VERSION 5.8 ;
BUSBITCHARS "[]" ;
DIVIDERCHAR "/" ;
UNITS
    DATABASE MICRONS 1000 ;
END UNITS

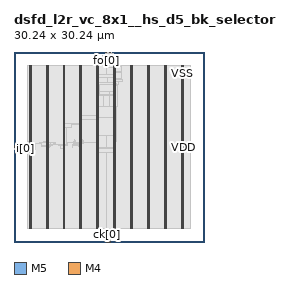
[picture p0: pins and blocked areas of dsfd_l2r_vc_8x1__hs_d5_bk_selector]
MACRO dsfd_l2r_vc_8x1__hs_d5_bk_selector
  FOREIGN dsfd_l2r_vc_8x1__hs_d5_bk_selector 0 0 ;
  CLASS BLOCK ;
  SIZE 30.24 BY 30.24 ;
  PIN ck[0]
    DIRECTION INPUT ;
    USE SIGNAL ;
    PORT
      LAYER M5 ;
        RECT  14.784 0 14.808 0.084 ;
    END
  END ck[0]
  PIN cks[0]
    DIRECTION INPUT ;
    USE SIGNAL ;
    PORT
      LAYER M5 ;
        RECT  14.976 0 15 0.084 ;
    END
  END cks[0]
  PIN fo[0]
    DIRECTION OUTPUT ;
    USE SIGNAL ;
    PORT
      LAYER M5 ;
        RECT  14.64 30.156 14.664 30.24 ;
    END
  END fo[0]
  PIN i[0]
    DIRECTION INPUT ;
    USE SIGNAL ;
    PORT
      LAYER M4 ;
        RECT  0 14.88 0.084 14.904 ;
    END
  END i[0]
  PIN i[1]
    DIRECTION INPUT ;
    USE SIGNAL ;
    PORT
      LAYER M4 ;
        RECT  0 14.928 0.084 14.952 ;
    END
  END i[1]
  PIN i[2]
    DIRECTION INPUT ;
    USE SIGNAL ;
    PORT
      LAYER M4 ;
        RECT  0 14.976 0.084 15 ;
    END
  END i[2]
  PIN i[3]
    DIRECTION INPUT ;
    USE SIGNAL ;
    PORT
      LAYER M4 ;
        RECT  0 15.024 0.084 15.048 ;
    END
  END i[3]
  PIN i[4]
    DIRECTION INPUT ;
    USE SIGNAL ;
    PORT
      LAYER M4 ;
        RECT  0 15.072 0.084 15.096 ;
    END
  END i[4]
  PIN i[5]
    DIRECTION INPUT ;
    USE SIGNAL ;
    PORT
      LAYER M4 ;
        RECT  0 15.12 0.084 15.144 ;
    END
  END i[5]
  PIN i[6]
    DIRECTION INPUT ;
    USE SIGNAL ;
    PORT
      LAYER M4 ;
        RECT  0 15.168 0.084 15.192 ;
    END
  END i[6]
  PIN i[7]
    DIRECTION INPUT ;
    USE SIGNAL ;
    PORT
      LAYER M4 ;
        RECT  0 15.216 0.084 15.24 ;
    END
  END i[7]
  PIN i[8]
    DIRECTION INPUT ;
    USE SIGNAL ;
    PORT
      LAYER M4 ;
        RECT  0 15.264 0.084 15.288 ;
    END
  END i[8]
  PIN od[0]
    DIRECTION OUTPUT ;
    USE SIGNAL ;
    PORT
      LAYER M5 ;
        RECT  14.832 30.156 14.856 30.24 ;
    END
  END od[0]
  PIN od[1]
    DIRECTION OUTPUT ;
    USE SIGNAL ;
    PORT
      LAYER M5 ;
        RECT  14.88 30.156 14.904 30.24 ;
    END
  END od[1]
  PIN od[2]
    DIRECTION OUTPUT ;
    USE SIGNAL ;
    PORT
      LAYER M5 ;
        RECT  14.928 30.156 14.952 30.24 ;
    END
  END od[2]
  PIN od[3]
    DIRECTION OUTPUT ;
    USE SIGNAL ;
    PORT
      LAYER M5 ;
        RECT  14.976 30.156 15 30.24 ;
    END
  END od[3]
  PIN od[4]
    DIRECTION OUTPUT ;
    USE SIGNAL ;
    PORT
      LAYER M5 ;
        RECT  15.024 30.156 15.048 30.24 ;
    END
  END od[4]
  PIN od[5]
    DIRECTION OUTPUT ;
    USE SIGNAL ;
    PORT
      LAYER M5 ;
        RECT  15.072 30.156 15.096 30.24 ;
    END
  END od[5]
  PIN od[6]
    DIRECTION OUTPUT ;
    USE SIGNAL ;
    PORT
      LAYER M5 ;
        RECT  15.12 30.156 15.144 30.24 ;
    END
  END od[6]
  PIN od[7]
    DIRECTION OUTPUT ;
    USE SIGNAL ;
    PORT
      LAYER M5 ;
        RECT  15.168 30.156 15.192 30.24 ;
    END
  END od[7]
  PIN od[8]
    DIRECTION OUTPUT ;
    USE SIGNAL ;
    PORT
      LAYER M5 ;
        RECT  15.216 30.156 15.24 30.24 ;
    END
  END od[8]
  PIN od[9]
    DIRECTION OUTPUT ;
    USE SIGNAL ;
    PORT
      LAYER M5 ;
        RECT  15.264 30.156 15.288 30.24 ;
    END
  END od[9]
  PIN rs[0]
    DIRECTION INPUT ;
    USE SIGNAL ;
    PORT
      LAYER M5 ;
        RECT  15.168 0 15.192 0.084 ;
    END
  END rs[0]
  PIN rss[0]
    DIRECTION INPUT ;
    USE SIGNAL ;
    PORT
      LAYER M5 ;
        RECT  15.36 0 15.384 0.084 ;
    END
  END rss[0]
  PIN st[0]
    DIRECTION OUTPUT ;
    USE SIGNAL ;
    PORT
      LAYER M5 ;
        RECT  15.456 30.156 15.48 30.24 ;
    END
  END st[0]
  PIN st[1]
    DIRECTION OUTPUT ;
    USE SIGNAL ;
    PORT
      LAYER M5 ;
        RECT  15.504 30.156 15.528 30.24 ;
    END
  END st[1]
  PIN st[2]
    DIRECTION OUTPUT ;
    USE SIGNAL ;
    PORT
      LAYER M5 ;
        RECT  15.552 30.156 15.576 30.24 ;
    END
  END st[2]
  PIN VDD
    DIRECTION INOUT ;
    USE POWER ;
    PORT
      LAYER M5 ;
        RECT  26.892 2.151 27.012 28.089 ;
        RECT  24.192 2.151 24.312 28.089 ;
        RECT  21.492 2.151 21.612 28.089 ;
        RECT  18.792 2.151 18.912 28.089 ;
        RECT  16.092 2.151 16.212 28.089 ;
        RECT  13.392 2.151 13.512 28.089 ;
        RECT  10.692 2.151 10.812 28.089 ;
        RECT  7.992 2.151 8.112 28.089 ;
        RECT  5.292 2.151 5.412 28.089 ;
        RECT  2.592 2.151 2.712 28.089 ;
    END
  END VDD
  PIN VSS
    DIRECTION INOUT ;
    USE GROUND ;
    PORT
      LAYER M5 ;
        RECT  26.7 2.137 26.82 28.103 ;
        RECT  24 2.137 24.12 28.103 ;
        RECT  21.3 2.137 21.42 28.103 ;
        RECT  18.6 2.137 18.72 28.103 ;
        RECT  15.9 2.137 16.02 28.103 ;
        RECT  13.2 2.137 13.32 28.103 ;
        RECT  10.5 2.137 10.62 28.103 ;
        RECT  7.8 2.137 7.92 28.103 ;
        RECT  5.1 2.137 5.22 28.103 ;
        RECT  2.4 2.137 2.52 28.103 ;
    END
  END VSS
  # OT_OBS_CLOSED layer=M5 d_um=1.536 added=13
  OBS
    LAYER RVTN ;
     RECT  2.16 2.16 28.08 2.295 ;
     RECT  2.16 2.565 28.08 2.835 ;
     RECT  2.16 3.105 28.08 3.375 ;
     RECT  2.16 3.645 28.08 3.915 ;
     RECT  2.16 4.185 28.08 4.455 ;
     RECT  2.16 4.725 28.08 4.995 ;
     RECT  2.16 5.265 28.08 5.535 ;
     RECT  2.16 5.805 28.08 6.075 ;
     RECT  2.16 6.345 28.08 6.615 ;
     RECT  2.16 6.885 28.08 7.155 ;
     RECT  2.16 7.425 28.08 7.695 ;
     RECT  2.16 7.965 28.08 8.235 ;
     RECT  2.16 8.505 28.08 8.775 ;
     RECT  2.16 9.045 28.08 9.315 ;
     RECT  2.16 9.585 28.08 9.855 ;
     RECT  2.16 10.125 28.08 10.395 ;
     RECT  2.16 10.665 28.08 10.935 ;
     RECT  2.16 11.205 28.08 11.475 ;
     RECT  2.16 11.745 28.08 12.015 ;
     RECT  2.16 12.285 28.08 12.555 ;
     RECT  2.16 12.825 28.08 13.095 ;
     RECT  2.16 13.365 28.08 13.635 ;
     RECT  2.16 13.905 28.08 14.175 ;
     RECT  2.16 14.445 28.08 14.715 ;
     RECT  2.16 14.985 28.08 15.255 ;
     RECT  2.16 15.525 28.08 15.795 ;
     RECT  2.16 16.065 28.08 16.335 ;
     RECT  2.16 16.605 28.08 16.875 ;
     RECT  2.16 17.145 28.08 17.415 ;
     RECT  2.16 17.685 28.08 17.955 ;
     RECT  2.16 18.225 28.08 18.495 ;
     RECT  2.16 18.765 28.08 19.035 ;
     RECT  2.16 19.305 28.08 19.575 ;
     RECT  2.16 19.845 28.08 20.115 ;
     RECT  2.16 20.385 28.08 20.655 ;
     RECT  2.16 20.925 28.08 21.195 ;
     RECT  2.16 21.465 28.08 21.735 ;
     RECT  2.16 22.005 28.08 22.275 ;
     RECT  2.16 22.545 28.08 22.815 ;
     RECT  2.16 23.085 28.08 23.355 ;
     RECT  2.16 23.625 28.08 23.895 ;
     RECT  2.16 24.165 28.08 24.435 ;
     RECT  2.16 24.705 28.08 24.975 ;
     RECT  2.16 25.245 28.08 25.515 ;
     RECT  2.16 25.785 28.08 26.055 ;
     RECT  2.16 26.325 28.08 26.595 ;
     RECT  2.16 26.865 28.08 27.135 ;
     RECT  2.16 27.405 28.08 27.675 ;
     RECT  2.16 27.945 28.08 28.08 ;
    LAYER RVTP ;
     RECT  2.16 2.295 28.08 2.565 ;
     RECT  2.16 2.835 28.08 3.105 ;
     RECT  2.16 3.375 28.08 3.645 ;
     RECT  2.16 3.915 28.08 4.185 ;
     RECT  2.16 4.455 28.08 4.725 ;
     RECT  2.16 4.995 28.08 5.265 ;
     RECT  2.16 5.535 28.08 5.805 ;
     RECT  2.16 6.075 28.08 6.345 ;
     RECT  2.16 6.615 28.08 6.885 ;
     RECT  2.16 7.155 28.08 7.425 ;
     RECT  2.16 7.695 28.08 7.965 ;
     RECT  2.16 8.235 28.08 8.505 ;
     RECT  2.16 8.775 28.08 9.045 ;
     RECT  2.16 9.315 28.08 9.585 ;
     RECT  2.16 9.855 28.08 10.125 ;
     RECT  2.16 10.395 28.08 10.665 ;
     RECT  2.16 10.935 28.08 11.205 ;
     RECT  2.16 11.475 28.08 11.745 ;
     RECT  2.16 12.015 28.08 12.285 ;
     RECT  2.16 12.555 28.08 12.825 ;
     RECT  2.16 13.095 28.08 13.365 ;
     RECT  2.16 13.635 28.08 13.905 ;
     RECT  2.16 14.175 28.08 14.445 ;
     RECT  2.16 14.715 28.08 14.985 ;
     RECT  2.16 15.255 28.08 15.525 ;
     RECT  2.16 15.795 28.08 16.065 ;
     RECT  2.16 16.335 28.08 16.605 ;
     RECT  2.16 16.875 28.08 17.145 ;
     RECT  2.16 17.415 28.08 17.685 ;
     RECT  2.16 17.955 28.08 18.225 ;
     RECT  2.16 18.495 28.08 18.765 ;
     RECT  2.16 19.035 28.08 19.305 ;
     RECT  2.16 19.575 28.08 19.845 ;
     RECT  2.16 20.115 28.08 20.385 ;
     RECT  2.16 20.655 28.08 20.925 ;
     RECT  2.16 21.195 28.08 21.465 ;
     RECT  2.16 21.735 28.08 22.005 ;
     RECT  2.16 22.275 28.08 22.545 ;
     RECT  2.16 22.815 28.08 23.085 ;
     RECT  2.16 23.355 28.08 23.625 ;
     RECT  2.16 23.895 28.08 24.165 ;
     RECT  2.16 24.435 28.08 24.705 ;
     RECT  2.16 24.975 28.08 25.245 ;
     RECT  2.16 25.515 28.08 25.785 ;
     RECT  2.16 26.055 28.08 26.325 ;
     RECT  2.16 26.595 28.08 26.865 ;
     RECT  2.16 27.135 28.08 27.405 ;
     RECT  2.16 27.675 28.08 27.945 ;
    LAYER M1 ;
     RECT  2.16 2.151 28.08 28.089 ;
    LAYER M2 ;
     RECT  0.139 14.76 0.175 14.778 ;
     RECT  0.175 14.688 0.347 15.282 ;
     RECT  0.347 14.688 0.491 15.21 ;
     RECT  0.491 14.688 2.16 14.778 ;
     RECT  2.16 2.151 28.08 28.089 ;
    LAYER M3 ;
     RECT  2.415 2.143 2.505 2.413 ;
     RECT  5.115 2.143 5.205 2.413 ;
     RECT  7.815 2.143 7.905 2.413 ;
     RECT  10.515 2.143 10.605 2.413 ;
     RECT  13.215 2.143 13.305 2.413 ;
     RECT  15.915 2.143 16.005 2.413 ;
     RECT  18.615 2.143 18.705 2.413 ;
     RECT  21.315 2.143 21.405 2.413 ;
     RECT  24.015 2.143 24.105 2.413 ;
     RECT  26.715 2.143 26.805 2.413 ;
     RECT  15.915 2.413 16.197 13.675 ;
     RECT  13.215 2.413 13.497 14.203 ;
     RECT  15.3 13.675 16.197 14.215 ;
     RECT  13.215 14.203 13.986 14.251 ;
     RECT  14.796 14.215 16.197 14.251 ;
     RECT  13.215 14.251 16.197 14.369 ;
     RECT  0.18 14.683 0.198 14.755 ;
     RECT  2.415 2.413 2.697 14.791 ;
     RECT  2.415 14.791 3.402 14.875 ;
     RECT  7.815 2.413 8.097 14.881 ;
     RECT  0.144 14.755 0.198 14.957 ;
     RECT  5.115 2.413 5.397 14.989 ;
     RECT  0.18 14.957 0.198 15.115 ;
     RECT  2.304 14.875 3.402 15.151 ;
     RECT  10.515 2.413 10.797 15.151 ;
     RECT  0.18 15.115 0.414 15.187 ;
     RECT  1.152 15.163 1.17 15.187 ;
     RECT  4.356 15.151 4.374 15.223 ;
     RECT  5.115 14.989 5.67 15.223 ;
     RECT  0.18 15.187 1.17 15.293 ;
     RECT  0.18 15.293 0.198 15.296 ;
     RECT  7.416 14.881 8.097 15.331 ;
     RECT  1.152 15.293 1.17 15.341 ;
     RECT  4.356 15.223 5.814 15.421 ;
     RECT  7.416 15.331 8.478 15.421 ;
     RECT  9.324 15.061 9.342 15.421 ;
     RECT  10.332 15.151 10.797 15.421 ;
     RECT  7.056 15.421 8.478 15.449 ;
     RECT  9.324 15.421 10.797 15.493 ;
     RECT  4.356 15.421 6.174 15.499 ;
     RECT  9.324 15.493 10.818 15.521 ;
     RECT  7.056 15.449 8.442 15.533 ;
     RECT  7.056 15.533 7.074 15.557 ;
     RECT  2.304 15.151 3.474 15.601 ;
     RECT  14.544 14.369 16.197 15.601 ;
     RECT  4.356 15.499 6.282 15.629 ;
     RECT  2.304 15.601 3.582 15.691 ;
     RECT  4.356 15.629 5.397 15.691 ;
     RECT  6.156 15.629 6.282 15.691 ;
     RECT  9.54 15.521 10.818 15.691 ;
     RECT  2.304 15.691 5.397 15.719 ;
     RECT  6.156 15.691 6.678 15.719 ;
     RECT  7.815 15.533 8.442 15.719 ;
     RECT  2.304 15.719 2.862 15.755 ;
     RECT  9.54 15.691 11.07 15.755 ;
     RECT  12.348 15.601 12.366 15.755 ;
     RECT  3.996 15.719 5.397 15.773 ;
     RECT  6.228 15.719 6.678 15.791 ;
     RECT  13.215 14.369 13.497 15.799 ;
     RECT  6.336 15.791 6.678 15.821 ;
     RECT  7.815 15.719 8.19 15.821 ;
     RECT  4.392 15.773 5.397 15.827 ;
     RECT  10.515 15.755 11.07 15.827 ;
     RECT  6.66 15.821 6.678 15.899 ;
     RECT  14.328 15.601 16.197 15.961 ;
     RECT  4.644 15.827 5.397 15.989 ;
     RECT  13.068 15.799 13.497 15.989 ;
     RECT  2.34 15.755 2.862 16.025 ;
     RECT  9.54 15.755 9.738 16.025 ;
     RECT  9.612 16.025 9.738 16.061 ;
     RECT  9.684 16.061 9.738 16.133 ;
     RECT  10.515 15.827 10.998 16.133 ;
     RECT  13.14 15.989 13.497 16.141 ;
     RECT  14.328 15.961 16.326 16.141 ;
     RECT  13.14 16.141 16.326 16.169 ;
     RECT  9.684 16.133 9.702 16.295 ;
     RECT  10.515 16.133 10.854 16.367 ;
     RECT  13.176 16.169 16.326 16.973 ;
     RECT  14.292 16.973 16.326 17.069 ;
     RECT  9.144 18.235 9.162 18.689 ;
     RECT  8.928 18.763 8.946 18.803 ;
     RECT  13.176 16.973 13.497 19.471 ;
     RECT  10.515 16.367 10.797 19.483 ;
     RECT  12.564 19.471 13.497 19.517 ;
     RECT  13.14 19.517 13.497 19.805 ;
     RECT  10.515 19.483 10.854 20.111 ;
     RECT  13.176 19.805 13.497 20.885 ;
     RECT  13.215 20.885 13.497 21.001 ;
     RECT  14.328 17.069 16.326 21.155 ;
     RECT  13.215 21.001 13.59 21.541 ;
     RECT  14.472 21.155 16.326 21.541 ;
     RECT  14.472 21.541 16.506 24.899 ;
     RECT  14.508 24.899 16.506 25.043 ;
     RECT  14.544 25.043 16.506 25.051 ;
     RECT  14.544 25.051 16.578 25.591 ;
     RECT  14.544 25.591 17.19 25.889 ;
     RECT  13.215 21.541 13.734 25.951 ;
     RECT  14.544 25.889 17.046 25.951 ;
     RECT  13.215 25.951 17.046 26.941 ;
     RECT  13.215 26.941 17.154 27.059 ;
     RECT  2.415 16.025 2.697 27.827 ;
     RECT  5.115 15.989 5.397 27.827 ;
     RECT  7.815 15.821 8.097 27.827 ;
     RECT  10.515 20.111 10.797 27.827 ;
     RECT  18.615 2.413 18.897 27.827 ;
     RECT  21.315 2.413 21.597 27.827 ;
     RECT  24.015 2.413 24.297 27.827 ;
     RECT  26.715 2.413 26.997 27.827 ;
     RECT  13.215 27.059 17.118 27.869 ;
     RECT  17.028 27.869 17.046 27.941 ;
     RECT  2.415 27.827 2.505 28.097 ;
     RECT  5.115 27.827 5.205 28.097 ;
     RECT  7.815 27.827 7.905 28.097 ;
     RECT  10.515 27.827 10.605 28.097 ;
     RECT  13.215 27.869 16.005 28.097 ;
     RECT  18.615 27.827 18.705 28.097 ;
     RECT  21.315 27.827 21.405 28.097 ;
     RECT  24.015 27.827 24.105 28.097 ;
     RECT  26.715 27.827 26.805 28.097 ;
     RECT  14.004 28.097 15.75 28.589 ;
     RECT  14.148 28.589 15.75 29.741 ;
     RECT  14.652 29.741 15.75 29.789 ;
     RECT  15.012 29.789 15.75 30.077 ;
    LAYER M4 ;
     RECT  0.06 14.88 0.133 15.288 ;
     RECT  0.133 14.88 2.408 15.384 ;
     RECT  2.408 2.148 2.512 28.092 ;
     RECT  2.512 2.418 2.704 27.822 ;
     RECT  2.704 14.976 2.765 15.336 ;
     RECT  2.765 15.264 2.873 15.336 ;
     RECT  2.873 15.264 3.413 15.288 ;
     RECT  3.985 15.744 4.381 15.768 ;
     RECT  4.381 15.744 4.417 15.816 ;
     RECT  4.417 15.36 5.108 15.816 ;
     RECT  5.108 2.148 5.212 28.092 ;
     RECT  5.212 2.418 5.404 27.822 ;
     RECT  5.404 15.456 5.825 15.816 ;
     RECT  5.825 15.504 6.365 15.816 ;
     RECT  6.365 15.504 7.808 15.528 ;
     RECT  7.808 2.148 7.912 28.092 ;
     RECT  7.912 2.418 8.104 27.822 ;
     RECT  8.104 15.504 8.387 15.816 ;
     RECT  8.104 18.24 9.173 18.792 ;
     RECT  9.173 18.768 10.357 18.792 ;
     RECT  8.387 15.792 10.508 15.816 ;
     RECT  10.357 18.768 10.508 19.608 ;
     RECT  10.508 2.148 10.612 28.092 ;
     RECT  10.612 2.418 10.804 27.822 ;
     RECT  10.804 15.792 10.973 16.104 ;
     RECT  10.973 15.792 13.093 15.816 ;
     RECT  13.093 14.928 13.208 15.816 ;
     RECT  10.804 19.488 13.208 20.088 ;
     RECT  13.208 2.148 13.312 28.092 ;
     RECT  13.312 2.418 13.504 28.092 ;
     RECT  13.504 19.776 13.619 20.088 ;
     RECT  13.504 23.328 13.708 23.736 ;
     RECT  13.504 14.208 14.041 14.952 ;
     RECT  13.504 16.944 14.243 17.64 ;
     RECT  14.137 29.712 14.425 29.736 ;
     RECT  13.504 24.864 14.569 25.032 ;
     RECT  14.041 14.928 14.573 14.952 ;
     RECT  14.425 29.664 14.597 29.736 ;
     RECT  14.597 29.664 14.636 29.784 ;
     RECT  14.243 17.616 14.645 17.64 ;
     RECT  14.636 29.616 14.723 29.784 ;
     RECT  14.641 26.736 14.725 26.76 ;
     RECT  13.619 20.064 14.819 20.088 ;
     RECT  14.569 24.864 14.821 25.416 ;
     RECT  13.993 28.56 14.821 28.584 ;
     RECT  14.723 29.664 14.917 29.784 ;
     RECT  14.821 27.792 14.965 28.584 ;
     RECT  13.708 23.328 15.109 23.448 ;
     RECT  14.821 24.864 15.109 26.136 ;
     RECT  14.965 27.312 15.155 28.584 ;
     RECT  14.917 29.664 15.251 30.072 ;
     RECT  14.957 21.6 15.253 21.624 ;
     RECT  15.251 29.952 15.293 30.072 ;
     RECT  15.155 27.312 15.617 28.488 ;
     RECT  15.293 30.048 15.761 30.072 ;
     RECT  15.157 13.68 15.908 13.704 ;
     RECT  15.253 15.984 15.908 16.008 ;
     RECT  15.253 21.6 15.908 22.2 ;
     RECT  15.109 23.328 15.908 26.136 ;
     RECT  15.617 27.312 15.908 28.092 ;
     RECT  15.908 2.148 16.012 28.092 ;
     RECT  16.012 2.418 16.204 27.822 ;
     RECT  16.204 25.2 16.265 25.224 ;
     RECT  18.608 2.148 18.712 28.092 ;
     RECT  18.712 2.418 18.904 27.822 ;
     RECT  21.308 2.148 21.412 28.092 ;
     RECT  21.412 2.418 21.604 27.822 ;
     RECT  24.008 2.148 24.112 28.092 ;
     RECT  24.112 2.418 24.304 27.822 ;
     RECT  26.708 2.148 26.812 28.092 ;
     RECT  26.812 2.418 27.004 27.822 ;
    LAYER M5 ;
     RECT  14.784 0.016 15.384 2.137 ;
     RECT  2.4 2.137 2.52 2.151 ;
     RECT  5.1 2.137 5.22 2.151 ;
     RECT  7.8 2.137 7.92 2.151 ;
     RECT  10.5 2.137 10.62 2.151 ;
     RECT  13.2 2.137 13.32 2.151 ;
     RECT  14.784 2.137 16.02 2.151 ;
     RECT  18.6 2.137 18.72 2.151 ;
     RECT  21.3 2.137 21.42 2.151 ;
     RECT  24 2.137 24.12 2.151 ;
     RECT  26.7 2.137 26.82 2.151 ;
     RECT  13.2 2.151 13.512 14.197 ;
     RECT  14.784 2.151 16.212 14.197 ;
     RECT  13.2 14.197 16.212 14.917 ;
     RECT  13.104 14.917 16.212 14.963 ;
     RECT  0.144 15.205 0.168 15.395 ;
     RECT  7.8 2.151 8.112 15.493 ;
     RECT  13.104 14.963 13.512 16.933 ;
     RECT  14.784 14.963 16.212 16.933 ;
     RECT  7.8 15.493 8.376 18.275 ;
     RECT  10.5 2.151 10.812 18.757 ;
     RECT  10.368 18.757 10.812 19.619 ;
     RECT  13.104 16.933 16.212 19.811 ;
     RECT  13.2 19.811 16.212 21.635 ;
     RECT  13.2 21.635 14.232 23.317 ;
     RECT  15.264 21.635 16.212 23.317 ;
     RECT  13.2 23.317 16.212 23.459 ;
     RECT  15.12 23.459 16.212 23.987 ;
     RECT  13.2 23.459 13.656 25.043 ;
     RECT  14.832 25.381 14.856 26.147 ;
     RECT  14.688 26.725 14.712 27.781 ;
     RECT  15.9 23.987 16.212 27.781 ;
     RECT  2.4 2.151 2.712 28.089 ;
     RECT  5.1 2.151 5.412 28.089 ;
     RECT  7.8 18.275 8.112 28.089 ;
     RECT  10.5 19.619 10.812 28.089 ;
     RECT  13.2 25.043 13.512 28.089 ;
     RECT  14.688 27.781 16.212 28.089 ;
     RECT  18.6 2.151 18.912 28.089 ;
     RECT  21.3 2.151 21.612 28.089 ;
     RECT  24 2.151 24.312 28.089 ;
     RECT  26.7 2.151 27.012 28.089 ;
     RECT  2.4 28.089 2.52 28.103 ;
     RECT  5.1 28.089 5.22 28.103 ;
     RECT  7.8 28.089 7.92 28.103 ;
     RECT  10.5 28.089 10.62 28.103 ;
     RECT  13.2 28.089 13.32 28.103 ;
     RECT  14.688 28.089 16.02 28.103 ;
     RECT  18.6 28.089 18.72 28.103 ;
     RECT  21.3 28.089 21.42 28.103 ;
     RECT  24 28.089 24.12 28.103 ;
     RECT  26.7 28.089 26.82 28.103 ;
     RECT  14.688 28.103 15.528 29.749 ;
     RECT  14.64 29.749 15.528 30.037 ;
     RECT  14.64 30.037 15.576 30.224 ;
     RECT  13.32 2.137 14.784 2.151 ;
     RECT  13.512 2.151 14.784 14.197 ;
     RECT  13.512 14.963 14.784 16.933 ;
     RECT  14.232 21.635 15.264 23.317 ;
     RECT  13.656 23.459 15.12 23.987 ;
     RECT  13.656 23.987 15.9 25.043 ;
     RECT  13.512 25.043 15.9 25.381 ;
     RECT  13.512 25.381 14.832 26.147 ;
     RECT  14.856 25.381 15.9 26.147 ;
     RECT  13.512 26.147 15.9 26.725 ;
     RECT  13.512 26.725 14.688 28.089 ;
     RECT  14.712 26.725 15.9 27.781 ;
     RECT  13.32 28.089 14.688 28.103 ;
  END
END dsfd_l2r_vc_8x1__hs_d5_bk_selector
END LIBRARY
